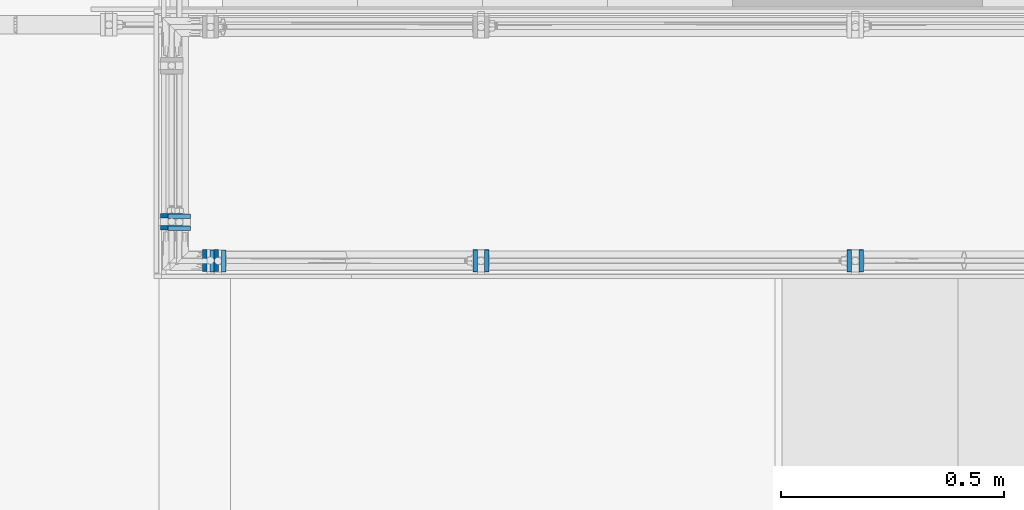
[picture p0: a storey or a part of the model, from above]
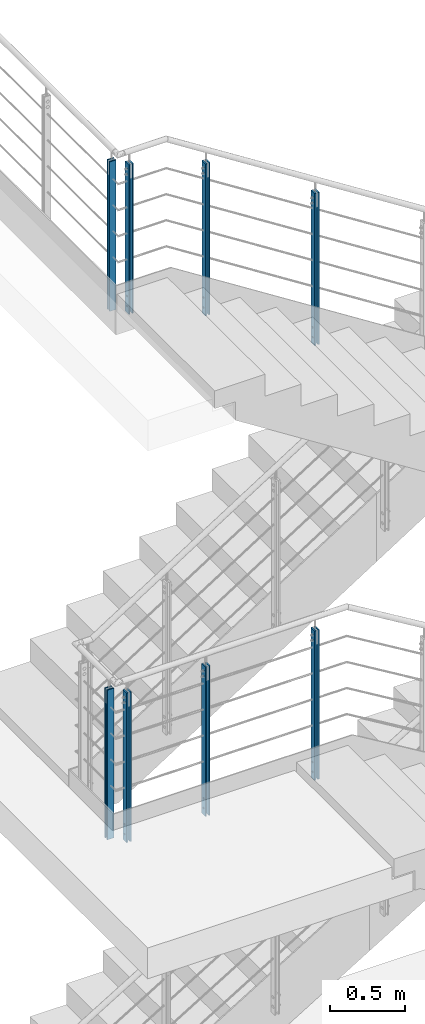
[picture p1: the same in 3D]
Properties of the parts of a building model (IFC2X3)

# File
Description: ViewDefinition[CoordinationView_V2.0]
File name: Treppengel?nder f?r Mercedes-Benz_ifc2x3.ifc
Time: 2026-07-12T18:14:45
Organization: Alpha 2 Mercedes-Benz
Written by: IFC Toolkit 2.0.26.0
Made in: Advance Steel 2024

# IfcBuildingStorey, Default Storey
In: Struktur 1
Elevation: 0 mm

# IfcBeam: - (135)
In: Default Storey
Name | Description = Section | Material | SectionFamily
128 x - | RD12 | S235JR | Round nach DIN
7 x - | RO42.4x3 | 1.4301 | Pipe_c nach DIN

# IfcBeam: Hand_Rail (5)
In: Default Storey
Description: RO42.4x3; Material: 1.4301
Pset_BeamCommon - Slope: 0 deg; IsExternal: no; LoadBearing: no
ProfileProperties - SectionFamily: Pipe_c nach DIN; Section: RO42.4x3
Name | Reference | Span (mm)
Hand_Rail | 68 | 441.4
Hand_Rail | 70 | 436.4
Hand_Rail | 72 | 437.4
Hand_Rail | 74 | 1800.95
Hand_Rail | 69 | 2241

# IfcBuildingElementProxy: - (9)
In: Default Storey
Material: 1.4301

# IfcColumn: - (74)
In: Default Storey
Name | Description = Section | Material | SectionFamily
36 x - | FL50X10 | S235JR | Flat nach DIN
37 x - | RD16 | 1.4301 | Round nach DIN
- | RO42.4x3 | 1.4301 | Pipe_c nach DIN

# IfcColumn: Gel?nder (36)
In: Default Storey
Description: FL50X10; Material: S235JR
Pset_ColumnCommon - Slope: 0 deg; IsExternal: no; LoadBearing: no
ProfileProperties - SectionFamily: Flat nach DIN; Section: FL50X10
Name | Reference
3 x Gel?nder | 30
6 x Gel?nder | 28
Gel?nder | 41
Gel?nder | 45
Gel?nder | 34
7 x Gel?nder | 27
Gel?nder | 42
Gel?nder | 40
Gel?nder | 39
Gel?nder | 33
Gel?nder | 32
4 x Gel?nder | 29
Gel?nder | 37
Gel?nder | 36
Gel?nder | 44
Gel?nder | 43
Gel?nder | 35
Gel?nder | 38
2 x Gel?nder | 31

# IfcColumn: Girder (2)
In: Default Storey
Description: FL50X10; Material: S235JR
Pset_ColumnCommon - Slope: 0 deg; IsExternal: no; LoadBearing: no
ProfileProperties - SectionFamily: Flat nach DIN; Section: FL50X10
Name | Reference
Girder | 25
Girder | 24

# IfcMechanicalFastener: - (74)
In: Default Storey
NominalDiameter: 12 mm; NominalLength: 55 mm

# IfcMember: - (73)
In: Default Storey
Name | Description = Section | Material | SectionFamily
72 x - | RD12 | S235JR | Round nach DIN
- | RO42.4x3 | 1.4301 | Pipe_c nach DIN

# IfcMember: Hand_Rail (3)
In: Default Storey
Description: RO42.4x3; Material: 1.4301
Pset_MemberCommon - Slope: 0 deg; IsExternal: no; LoadBearing: no
ProfileProperties - SectionFamily: Pipe_c nach DIN; Section: RO42.4x3
Name | Reference | Span (mm)
Hand_Rail | 73 | 3010.69
Hand_Rail | 71 | 5007.04
Hand_Rail | 67 | 5569.31

# IfcPlate: - (88)
In: Default Storey
Description: -
Pset_PlateCommon - IsExternal: no; LoadBearing: no
Name | Material | Reference
33 x - | S235JR 16 mm | 100
37 x - | 1.4301 16 mm | 176
4 x - | S235JR 16 mm | 101
- | S235JR 10 mm | 12
- | S235JR 10 mm | 10
- | S235JR 10 mm | 1
- | S235JR 10 mm | 7
- | S235JR 10 mm | 3
- | S235JR 10 mm | 2
- | S235JR 10 mm | 5
- | S235JR 10 mm | 4
- | S235JR 10 mm | 6
- | S235JR 10 mm | 180
- | S235JR 10 mm | 85
- | S235JR 10 mm | 181
- | S235JR 10 mm | 8
- | S235JR 10 mm | 11

# IfcSlab: - (5)
In: Default Storey
Description: -; Material: C25/30 250 mm
Pset_SlabCommon - Reference: nicht definiert; IsExternal: no; LoadBearing: no; Combustible: no; Compartmentation: no; PitchAngle: 0 deg

# IfcWall: - (4)
In: Default Storey
Description: -; Material: C25/30 1300 mm
Pset_WallCommon - Reference: nicht definiert; Combustible: no; IsExternal: no; ExtendToStructure: no; LoadBearing: no; Compartmentation: no
